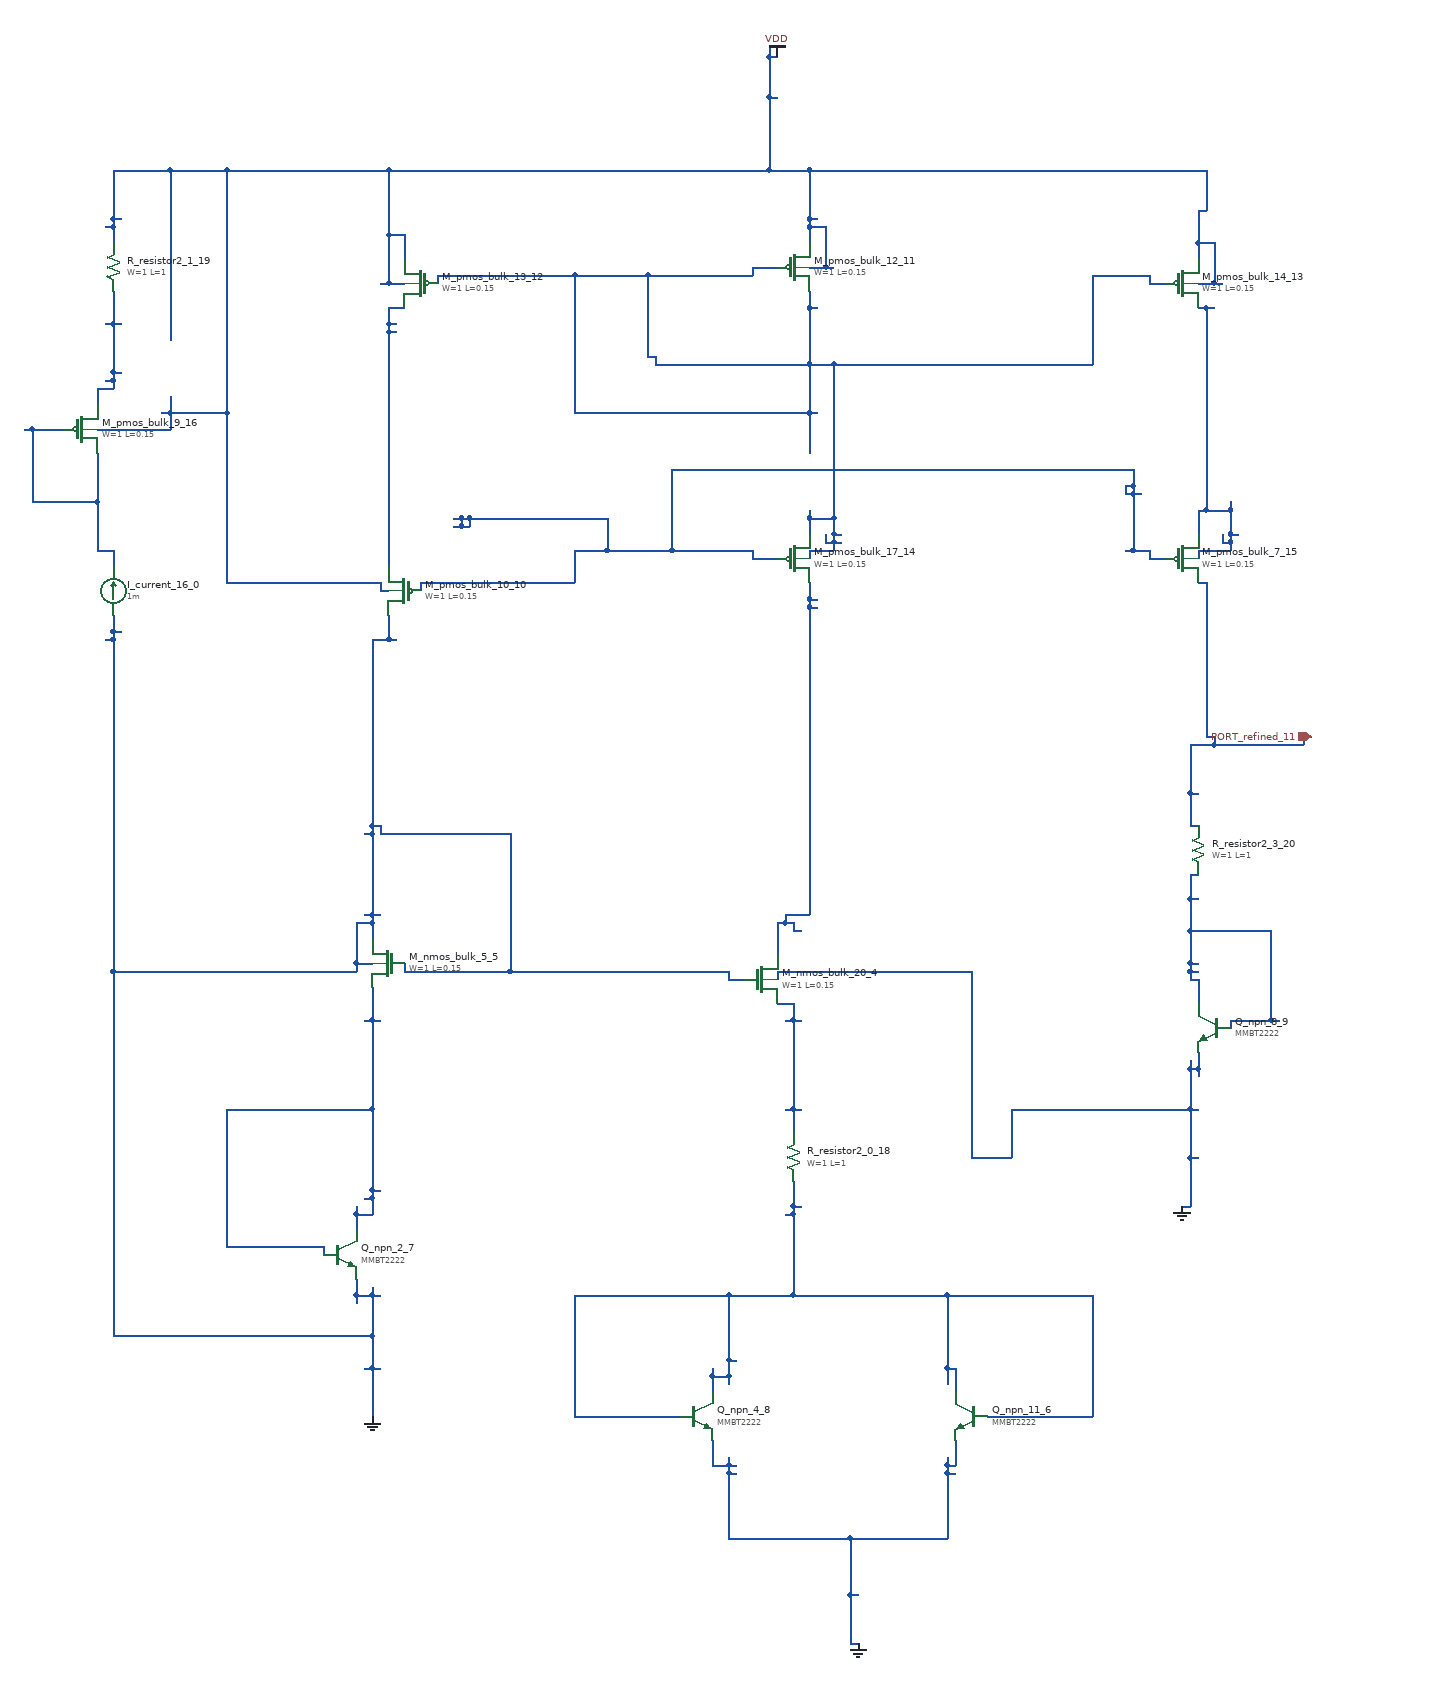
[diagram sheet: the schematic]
v {xschem version=3.4.8 file_version=1.2}
G {}
K {}
V {}
S {}
E {}
C {devices/isource.sym} 320 740 2 0 {name="I_current_16_0" value=1m}
C {devices/gnd.sym} 1640 1500 0 0 {name="l_gnd_15_1" lab="GND"}
C {devices/gnd.sym} 1240 2040 0 0 {name="l_gnd_18_2" lab="GND"}
C {devices/gnd.sym} 640 1760 0 0 {name="l_gnd_19_3" lab="GND"}
C {sky130_fd_pr/nfet_01v8.sym} 1120 1220 0 0 {name="M_nmos_bulk_20_4"
W=1
L=0.15
nf=1 
mult=1
ad="expr('int((@nf + 1)/2) * @W / @nf * 0.29')"
pd="expr('2*int((@nf + 1)/2) * (@W / @nf + 0.29)')"
as="expr('int((@nf + 2)/2) * @W / @nf * 0.29')"
ps="expr('2*int((@nf + 2)/2) * (@W / @nf + 0.29)')"
nrd="expr('0.29 / @W ')" nrs="expr('0.29 / @W ')"
sa=0 sb=0 sd=0
model=nfet_01v8
spiceprefix=X
}
C {sky130_fd_pr/nfet_01v8.sym} 660 1200 0 1 {name="M_nmos_bulk_5_5"
W=1
L=0.15
nf=1 
mult=1
ad="expr('int((@nf + 1)/2) * @W / @nf * 0.29')"
pd="expr('2*int((@nf + 1)/2) * (@W / @nf + 0.29)')"
as="expr('int((@nf + 2)/2) * @W / @nf * 0.29')"
ps="expr('2*int((@nf + 2)/2) * (@W / @nf + 0.29)')"
nrd="expr('0.29 / @W ')" nrs="expr('0.29 / @W ')"
sa=0 sb=0 sd=0
model=nfet_01v8
spiceprefix=X
}
C {devices/npn.sym} 1380 1760 0 1 {name="Q_npn_11_6"
model=MMBT2222
device=MMBT2222
footprint=SOT23
area=1
m=1}
C {devices/npn.sym} 600 1560 0 0 {name="Q_npn_2_7"
model=MMBT2222
device=MMBT2222
footprint=SOT23
area=1
m=1}
C {devices/npn.sym} 1040 1760 0 0 {name="Q_npn_4_8"
model=MMBT2222
device=MMBT2222
footprint=SOT23
area=1
m=1}
C {devices/npn.sym} 1680 1280 0 1 {name="Q_npn_8_9"
model=MMBT2222
device=MMBT2222
footprint=SOT23
area=1
m=1}
C {sky130_fd_pr/pfet_01v8.sym} 680 740 0 1 {name="M_pmos_bulk_10_10"
W=1
L=0.15
nf=1
mult=1
ad="expr('int((@nf + 1)/2) * @W / @nf * 0.29')"
pd="expr('2*int((@nf + 1)/2) * (@W / @nf + 0.29)')"
as="expr('int((@nf + 2)/2) * @W / @nf * 0.29')"
ps="expr('2*int((@nf + 2)/2) * (@W / @nf + 0.29)')"
nrd="expr('0.29 / @W ')" nrs="expr('0.29 / @W ')"
sa=0 sb=0 sd=0
model=pfet_01v8
spiceprefix=X
}
C {sky130_fd_pr/pfet_01v8.sym} 1160 340 0 0 {name="M_pmos_bulk_12_11"
W=1
L=0.15
nf=1
mult=1
ad="expr('int((@nf + 1)/2) * @W / @nf * 0.29')"
pd="expr('2*int((@nf + 1)/2) * (@W / @nf + 0.29)')"
as="expr('int((@nf + 2)/2) * @W / @nf * 0.29')"
ps="expr('2*int((@nf + 2)/2) * (@W / @nf + 0.29)')"
nrd="expr('0.29 / @W ')" nrs="expr('0.29 / @W ')"
sa=0 sb=0 sd=0
model=pfet_01v8
spiceprefix=X
}
C {sky130_fd_pr/pfet_01v8.sym} 700 360 0 1 {name="M_pmos_bulk_13_12"
W=1
L=0.15
nf=1
mult=1
ad="expr('int((@nf + 1)/2) * @W / @nf * 0.29')"
pd="expr('2*int((@nf + 1)/2) * (@W / @nf + 0.29)')"
as="expr('int((@nf + 2)/2) * @W / @nf * 0.29')"
ps="expr('2*int((@nf + 2)/2) * (@W / @nf + 0.29)')"
nrd="expr('0.29 / @W ')" nrs="expr('0.29 / @W ')"
sa=0 sb=0 sd=0
model=pfet_01v8
spiceprefix=X
}
C {sky130_fd_pr/pfet_01v8.sym} 1640 360 0 0 {name="M_pmos_bulk_14_13"
W=1
L=0.15
nf=1
mult=1
ad="expr('int((@nf + 1)/2) * @W / @nf * 0.29')"
pd="expr('2*int((@nf + 1)/2) * (@W / @nf + 0.29)')"
as="expr('int((@nf + 2)/2) * @W / @nf * 0.29')"
ps="expr('2*int((@nf + 2)/2) * (@W / @nf + 0.29)')"
nrd="expr('0.29 / @W ')" nrs="expr('0.29 / @W ')"
sa=0 sb=0 sd=0
model=pfet_01v8
spiceprefix=X
}
C {sky130_fd_pr/pfet_01v8.sym} 1160 700 0 0 {name="M_pmos_bulk_17_14"
W=1
L=0.15
nf=1
mult=1
ad="expr('int((@nf + 1)/2) * @W / @nf * 0.29')"
pd="expr('2*int((@nf + 1)/2) * (@W / @nf + 0.29)')"
as="expr('int((@nf + 2)/2) * @W / @nf * 0.29')"
ps="expr('2*int((@nf + 2)/2) * (@W / @nf + 0.29)')"
nrd="expr('0.29 / @W ')" nrs="expr('0.29 / @W ')"
sa=0 sb=0 sd=0
model=pfet_01v8
spiceprefix=X
}
C {sky130_fd_pr/pfet_01v8.sym} 1640 700 0 0 {name="M_pmos_bulk_7_15"
W=1
L=0.15
nf=1
mult=1
ad="expr('int((@nf + 1)/2) * @W / @nf * 0.29')"
pd="expr('2*int((@nf + 1)/2) * (@W / @nf + 0.29)')"
as="expr('int((@nf + 2)/2) * @W / @nf * 0.29')"
ps="expr('2*int((@nf + 2)/2) * (@W / @nf + 0.29)')"
nrd="expr('0.29 / @W ')" nrs="expr('0.29 / @W ')"
sa=0 sb=0 sd=0
model=pfet_01v8
spiceprefix=X
}
C {sky130_fd_pr/pfet_01v8.sym} 280 540 0 0 {name="M_pmos_bulk_9_16"
W=1
L=0.15
nf=1
mult=1
ad="expr('int((@nf + 1)/2) * @W / @nf * 0.29')"
pd="expr('2*int((@nf + 1)/2) * (@W / @nf + 0.29)')"
as="expr('int((@nf + 2)/2) * @W / @nf * 0.29')"
ps="expr('2*int((@nf + 2)/2) * (@W / @nf + 0.29)')"
nrd="expr('0.29 / @W ')" nrs="expr('0.29 / @W ')"
sa=0 sb=0 sd=0
model=pfet_01v8
spiceprefix=X
}
C {devices/ipin.sym} 1800 920 0 0 {name="p_port_6_17" lab="PORT_refined_11"}
C {sky130_fd_pr/res_generic_po.sym} 1160 1440 2 0 {name="R_resistor2_0_18"
W=1
L=1
model=res_generic_po
spiceprefix=X
mult=1}
C {sky130_fd_pr/res_generic_po.sym} 320 340 2 0 {name="R_resistor2_1_19"
W=1
L=1
model=res_generic_po
spiceprefix=X
mult=1}
C {sky130_fd_pr/res_generic_po.sym} 1660 1060 2 0 {name="R_resistor2_3_20"
W=1
L=1
model=res_generic_po
spiceprefix=X
mult=1}
C {devices/vdd.sym} 1140 80 0 0 {name="l_vdd_21_21" lab="VDD"}
N 1230 2040 1240 2040 {}
N 1230 1980 1240 1980 {}
N 1080 1910 1230 1910 {}
N 1230 1910 1350 1910 {}
N 1080 1830 1090 1830 {}
N 1350 1830 1360 1830 {}
N 1060 1820 1080 1820 {}
N 1080 1820 1090 1820 {}
N 1350 1820 1360 1820 {}
N 630 1700 640 1700 {}
N 640 1700 650 1700 {}
N 320 1660 640 1660 {}
N 620 1610 640 1610 {}
N 640 1610 650 1610 {}
N 1640 1500 1650 1500 {}
N 1380 1440 1430 1440 {}
N 1650 1440 1660 1440 {}
N 1430 1380 1650 1380 {}
N 1650 1380 1660 1380 {}
N 1650 1330 1660 1330 {}
N 1080 1220 1100 1220 {}
N 320 1210 620 1210 {}
N 680 1210 810 1210 {}
N 810 1210 1080 1210 {}
N 1140 1210 1380 1210 {}
N 620 1200 640 1200 {}
N 620 1150 640 1150 {}
N 630 1140 640 1140 {}
N 640 1140 650 1140 {}
N 630 1040 640 1040 {}
N 650 1040 810 1040 {}
N 640 1030 650 1030 {}
N 310 800 320 800 {}
N 640 800 660 800 {}
N 660 800 670 800 {}
N 320 790 330 790 {}
N 320 1660 320 1210 {}
N 320 1210 320 800 {}
N 320 800 320 790 {}
N 320 790 320 770 {}
N 620 1620 620 1610 {}
N 620 1610 620 1590 {}
N 620 1210 620 1200 {}
N 620 1200 620 1150 {}
N 640 1760 640 1700 {}
N 640 1700 640 1660 {}
N 640 1660 640 1610 {}
N 640 1610 640 1600 {}
N 640 1170 640 1150 {}
N 640 1150 640 1140 {}
N 640 1140 640 1040 {}
N 640 1040 640 1030 {}
N 640 1030 640 800 {}
N 650 1040 650 1030 {}
N 660 800 660 770 {}
N 680 1210 680 1200 {}
N 810 1210 810 1040 {}
N 1060 1820 1060 1790 {}
N 1080 1910 1080 1830 {}
N 1080 1830 1080 1820 {}
N 1080 1820 1080 1810 {}
N 1080 1220 1080 1210 {}
N 1140 1220 1140 1210 {}
N 1230 2040 1230 1980 {}
N 1230 1980 1230 1910 {}
N 1350 1910 1350 1830 {}
N 1350 1830 1350 1820 {}
N 1350 1820 1350 1810 {}
N 1360 1820 1360 1790 {}
N 1380 1440 1380 1210 {}
N 1430 1440 1430 1380 {}
N 1650 1500 1650 1440 {}
N 1650 1440 1650 1380 {}
N 1650 1380 1650 1330 {}
N 1650 1330 1650 1320 {}
N 1660 1340 1660 1330 {}
N 1660 1330 1660 1310 {}
N 300 690 320 690 {}
N 220 630 300 630 {}
N 210 540 220 540 {}
N 220 540 260 540 {}
N 220 630 220 540 {}
N 300 690 300 630 {}
N 300 630 300 570 {}
N 320 710 320 690 {}
N 1160 1160 1170 1160 {}
N 1140 1150 1150 1150 {}
N 1150 1150 1160 1150 {}
N 1150 1140 1180 1140 {}
N 1180 760 1190 760 {}
N 1180 750 1190 750 {}
N 1140 1190 1140 1150 {}
N 1150 1150 1150 1140 {}
N 1160 1160 1160 1150 {}
N 1180 1140 1180 760 {}
N 1180 760 1180 750 {}
N 1180 750 1180 730 {}
N 1650 1030 1660 1030 {}
N 1650 990 1660 990 {}
N 1650 930 1680 930 {}
N 1680 930 1790 930 {}
N 1670 920 1680 920 {}
N 1790 920 1800 920 {}
N 1660 730 1670 730 {}
N 1650 1030 1650 990 {}
N 1650 990 1650 930 {}
N 1670 920 1670 730 {}
N 1680 930 1680 920 {}
N 1790 930 1790 920 {}
N 300 490 320 490 {}
N 310 480 320 480 {}
N 320 470 330 470 {}
N 310 410 320 410 {}
N 320 410 330 410 {}
N 300 510 300 490 {}
N 320 490 320 480 {}
N 320 480 320 470 {}
N 320 470 320 410 {}
N 320 410 320 370 {}
N 1150 1380 1160 1380 {}
N 1160 1380 1170 1380 {}
N 1150 1270 1160 1270 {}
N 1160 1270 1170 1270 {}
N 1140 1250 1160 1250 {}
N 1160 1410 1160 1380 {}
N 1160 1380 1160 1270 {}
N 1160 1270 1160 1250 {}
N 460 1550 580 1550 {}
N 620 1510 640 1510 {}
N 630 1490 640 1490 {}
N 640 1480 650 1480 {}
N 460 1380 640 1380 {}
N 630 1270 640 1270 {}
N 640 1270 650 1270 {}
N 460 1550 460 1380 {}
N 580 1560 580 1550 {}
N 620 1530 620 1510 {}
N 620 1510 620 1500 {}
N 640 1510 640 1490 {}
N 640 1490 640 1480 {}
N 640 1480 640 1380 {}
N 640 1380 640 1270 {}
N 640 1270 640 1230 {}
N 890 1760 1020 1760 {}
N 1400 1760 1530 1760 {}
N 1060 1710 1080 1710 {}
N 1350 1700 1360 1700 {}
N 1080 1690 1090 1690 {}
N 890 1610 1080 1610 {}
N 1080 1610 1160 1610 {}
N 1160 1610 1350 1610 {}
N 1350 1610 1530 1610 {}
N 1150 1510 1160 1510 {}
N 1160 1500 1170 1500 {}
N 890 1760 890 1610 {}
N 1060 1730 1060 1710 {}
N 1060 1710 1060 1700 {}
N 1080 1720 1080 1710 {}
N 1080 1710 1080 1690 {}
N 1080 1690 1080 1610 {}
N 1160 1610 1160 1510 {}
N 1160 1510 1160 1500 {}
N 1160 1500 1160 1470 {}
N 1350 1720 1350 1700 {}
N 1350 1700 1350 1610 {}
N 1360 1730 1360 1700 {}
N 1530 1760 1530 1610 {}
N 1700 1270 1750 1270 {}
N 1750 1270 1760 1270 {}
N 1650 1220 1660 1220 {}
N 1650 1210 1660 1210 {}
N 1650 1200 1660 1200 {}
N 1650 1160 1750 1160 {}
N 1650 1120 1660 1120 {}
N 1650 1090 1660 1090 {}
N 1650 1220 1650 1210 {}
N 1650 1210 1650 1200 {}
N 1650 1200 1650 1160 {}
N 1650 1160 1650 1120 {}
N 1650 1120 1650 1090 {}
N 1660 1250 1660 1220 {}
N 1700 1280 1700 1270 {}
N 1750 1270 1750 1160 {}
N 650 740 660 740 {}
N 460 730 650 730 {}
N 300 540 390 540 {}
N 380 520 390 520 {}
N 390 520 460 520 {}
N 650 360 660 360 {}
N 660 360 680 360 {}
N 1660 360 1680 360 {}
N 1680 360 1690 360 {}
N 1180 340 1200 340 {}
N 1200 340 1210 340 {}
N 1660 310 1680 310 {}
N 660 300 680 300 {}
N 310 290 320 290 {}
N 1180 290 1200 290 {}
N 320 280 330 280 {}
N 1180 280 1190 280 {}
N 1660 270 1670 270 {}
N 320 220 390 220 {}
N 390 220 460 220 {}
N 460 220 660 220 {}
N 660 220 1130 220 {}
N 1130 220 1180 220 {}
N 1180 220 1670 220 {}
N 1130 130 1140 130 {}
N 1130 80 1140 80 {}
N 320 310 320 290 {}
N 320 290 320 280 {}
N 320 280 320 220 {}
N 390 540 390 520 {}
N 390 520 390 500 {}
N 390 430 390 220 {}
N 460 730 460 520 {}
N 460 520 460 220 {}
N 650 740 650 730 {}
N 660 360 660 300 {}
N 660 300 660 220 {}
N 680 330 680 300 {}
N 1130 220 1130 130 {}
N 1130 130 1130 80 {}
N 1130 80 1130 70 {}
N 1180 310 1180 290 {}
N 1180 290 1180 280 {}
N 1180 280 1180 220 {}
N 1200 340 1200 290 {}
N 1660 330 1660 310 {}
N 1660 310 1660 270 {}
N 1670 270 1670 220 {}
N 1680 360 1680 310 {}
N 700 730 890 730 {}
N 1110 700 1140 700 {}
N 1600 700 1620 700 {}
N 890 690 930 690 {}
N 930 690 1010 690 {}
N 1010 690 1110 690 {}
N 1570 690 1580 690 {}
N 1580 690 1600 690 {}
N 740 660 750 660 {}
N 750 660 760 660 {}
N 740 650 750 650 {}
N 750 650 760 650 {}
N 760 650 930 650 {}
N 1570 620 1580 620 {}
N 1580 620 1590 620 {}
N 1570 610 1580 610 {}
N 1010 590 1580 590 {}
N 700 740 700 730 {}
N 750 660 750 650 {}
N 760 660 760 650 {}
N 890 730 890 690 {}
N 930 690 930 650 {}
N 1010 690 1010 590 {}
N 1110 700 1110 690 {}
N 1570 620 1570 610 {}
N 1580 690 1580 620 {}
N 1580 620 1580 610 {}
N 1580 610 1580 590 {}
N 1600 700 1600 690 {}
N 1180 690 1210 690 {}
N 1200 680 1210 680 {}
N 1210 680 1220 680 {}
N 1210 670 1220 670 {}
N 1180 650 1210 650 {}
N 890 520 1180 520 {}
N 1180 520 1190 520 {}
N 990 460 1180 460 {}
N 1180 460 1210 460 {}
N 1210 460 1530 460 {}
N 980 450 990 450 {}
N 1180 390 1190 390 {}
N 1600 360 1620 360 {}
N 720 350 890 350 {}
N 890 350 980 350 {}
N 980 350 1110 350 {}
N 1530 350 1600 350 {}
N 1110 340 1140 340 {}
N 720 360 720 350 {}
N 890 520 890 350 {}
N 980 450 980 350 {}
N 990 460 990 450 {}
N 1110 350 1110 340 {}
N 1180 700 1180 690 {}
N 1180 670 1180 650 {}
N 1180 650 1180 640 {}
N 1180 570 1180 520 {}
N 1180 520 1180 460 {}
N 1180 460 1180 390 {}
N 1180 390 1180 370 {}
N 1200 680 1200 670 {}
N 1210 690 1210 680 {}
N 1210 680 1210 670 {}
N 1210 670 1210 650 {}
N 1210 650 1210 460 {}
N 1530 460 1530 350 {}
N 1600 360 1600 350 {}
N 660 420 670 420 {}
N 660 410 670 410 {}
N 660 390 680 390 {}
N 660 710 660 420 {}
N 660 420 660 410 {}
N 660 410 660 390 {}
N 1660 690 1700 690 {}
N 1690 680 1700 680 {}
N 1700 670 1710 670 {}
N 1660 640 1670 640 {}
N 1670 640 1700 640 {}
N 1660 390 1670 390 {}
N 1670 390 1680 390 {}
N 1660 700 1660 690 {}
N 1660 670 1660 640 {}
N 1670 640 1670 390 {}
N 1690 680 1690 670 {}
N 1700 690 1700 680 {}
N 1700 680 1700 670 {}
N 1700 670 1700 640 {}
N 1700 640 1700 630 {}
